VERSION 5.8 ;
BUSBITCHARS "[]" ;
DIVIDERCHAR "/" ;
CLEARANCEMEASURE EUCLIDEAN ;

SITE coresite_DH_P
    SIZE 0.0450 BY 0.2880 ;
    CLASS CORE ;
    SYMMETRY X Y ;
END coresite_DH_P

SITE coresite_DH_N
    SIZE 0.0450 BY 0.2880 ;
    CLASS CORE ;
    SYMMETRY X Y ;
END coresite_DH_N

SITE coresite
    SIZE 0.0450 BY 0.1440 ;
    CLASS CORE ;
    SYMMETRY X Y ;
END coresite

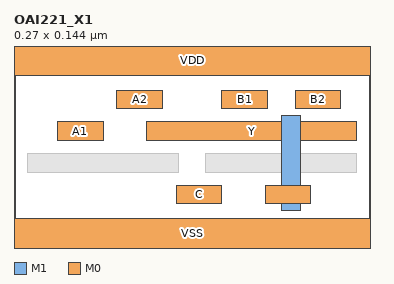
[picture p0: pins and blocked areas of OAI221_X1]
MACRO OAI221_X1
  CLASS CORE ;
  ORIGIN 0 0 ;
  FOREIGN OAI221_X1 0 0 ;
  SIZE 0.2700 BY 0.1440 ;
  SYMMETRY X Y ;
  SITE coresite ;
  PIN Y
    DIRECTION OUTPUT ;
    USE SIGNAL ;
    PORT
      LAYER M1 ;
        RECT 0.2025 0.0960 0.2175 0.0240 ;
      LAYER M0 ;
        RECT 0.1905 0.0430 0.2250 0.0290 ;
        RECT 0.1005 0.0910 0.2595 0.0770 ;
    END
  END Y
  PIN C
    DIRECTION INPUT ;
    USE SIGNAL ;
    PORT
      LAYER M0 ;
        RECT 0.1230 0.0430 0.1575 0.0290 ;
    END
  END C
  PIN A1
    DIRECTION INPUT ;
    USE SIGNAL ;
    PORT
      LAYER M0 ;
        RECT 0.0330 0.0910 0.0675 0.0770 ;
    END
  END A1
  PIN A2
    DIRECTION INPUT ;
    USE SIGNAL ;
    PORT
      LAYER M0 ;
        RECT 0.0780 0.1150 0.1125 0.1010 ;
    END
  END A2
  PIN B1
    DIRECTION INPUT ;
    USE SIGNAL ;
    PORT
      LAYER M0 ;
        RECT 0.1575 0.1150 0.1920 0.1010 ;
    END
  END B1
  PIN B2
    DIRECTION INPUT ;
    USE SIGNAL ;
    PORT
      LAYER M0 ;
        RECT 0.2130 0.1150 0.2475 0.1010 ;
    END
  END B2
  PIN VDD
    DIRECTION INOUT ;
    USE POWER ;
    SHAPE ABUTMENT ;
    PORT
      LAYER M0 ;
        RECT 0.0000 0.1260 0.2700 0.1620 ;
    END
  END VDD
  PIN VSS
    DIRECTION INOUT ;
    USE GROUND ;
    SHAPE ABUTMENT ;
    PORT
      LAYER M0 ;
        RECT 0.0000 -0.0180 0.2700 0.0180 ;
    END
  END VSS
  OBS
      LAYER V0 ;
        RECT 0.2030 0.0770 0.2170 0.0910 ;
        RECT 0.2030 0.0290 0.2170 0.0430 ;
      LAYER M0 ;
        RECT 0.0105 0.0530 0.1245 0.0670 ;
        RECT 0.1455 0.0530 0.2595 0.0670 ;
  END
END OAI221_X1

END LIBRARY
